VERSION 5.7 ;
  NOWIREEXTENSIONATPIN ON ;
  DIVIDERCHAR "/" ;
  BUSBITCHARS "[]" ;
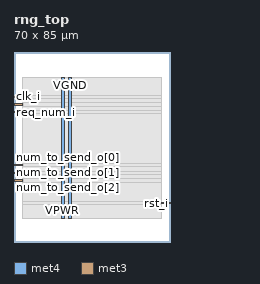
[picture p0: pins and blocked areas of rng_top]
MACRO rng_top
  CLASS BLOCK ;
  FOREIGN rng_top ;
  ORIGIN 0.000 0.000 ;
  SIZE 70.000 BY 85.000 ;
  PIN VGND
    DIRECTION INOUT ;
    USE GROUND ;
    PORT
      LAYER met4 ;
        RECT 24.340 10.640 25.940 73.680 ;
    END
  END VGND
  PIN VPWR
    DIRECTION INOUT ;
    USE POWER ;
    PORT
      LAYER met4 ;
        RECT 21.040 10.640 22.640 73.680 ;
    END
  END VPWR
  PIN clk_i
    DIRECTION INPUT ;
    USE SIGNAL ;
    ANTENNAGATEAREA 0.852000 ;
    PORT
      LAYER met3 ;
        RECT 0.000 64.640 4.000 65.240 ;
    END
  END clk_i
  PIN num_to_send_o[0]
    DIRECTION OUTPUT ;
    USE SIGNAL ;
    ANTENNADIFFAREA 0.445500 ;
    PORT
      LAYER met3 ;
        RECT 0.000 34.040 4.000 34.640 ;
    END
  END num_to_send_o[0]
  PIN num_to_send_o[1]
    DIRECTION OUTPUT ;
    USE SIGNAL ;
    ANTENNADIFFAREA 0.445500 ;
    PORT
      LAYER met3 ;
        RECT 0.000 30.640 4.000 31.240 ;
    END
  END num_to_send_o[1]
  PIN num_to_send_o[2]
    DIRECTION OUTPUT ;
    USE SIGNAL ;
    ANTENNADIFFAREA 0.445500 ;
    PORT
      LAYER met3 ;
        RECT 0.000 27.240 4.000 27.840 ;
    END
  END num_to_send_o[2]
  PIN req_num_i
    DIRECTION INPUT ;
    USE SIGNAL ;
    ANTENNAGATEAREA 0.196500 ;
    PORT
      LAYER met3 ;
        RECT 0.000 57.840 4.000 58.440 ;
    END
  END req_num_i
  PIN rst_i
    DIRECTION INPUT ;
    USE SIGNAL ;
    ANTENNAGATEAREA 0.196500 ;
    PORT
      LAYER met3 ;
        RECT 66.000 17.040 70.000 17.640 ;
    END
  END rst_i
  PIN wr_i
    DIRECTION INPUT ;
    USE SIGNAL ;
    ANTENNAGATEAREA 0.196500 ;
    PORT
      LAYER met3 ;
        RECT 0.000 61.240 4.000 61.840 ;
    END
  END wr_i
  OBS
      LAYER nwell ;
        RECT 5.330 10.795 64.590 73.630 ;
      LAYER li1 ;
        RECT 5.520 10.795 64.400 73.525 ;
      LAYER met1 ;
        RECT 4.210 10.640 64.400 73.680 ;
      LAYER met2 ;
        RECT 4.230 10.695 62.930 73.625 ;
      LAYER met3 ;
        RECT 3.990 65.640 66.000 73.605 ;
        RECT 4.400 64.240 66.000 65.640 ;
        RECT 3.990 62.240 66.000 64.240 ;
        RECT 4.400 60.840 66.000 62.240 ;
        RECT 3.990 58.840 66.000 60.840 ;
        RECT 4.400 57.440 66.000 58.840 ;
        RECT 3.990 35.040 66.000 57.440 ;
        RECT 4.400 33.640 66.000 35.040 ;
        RECT 3.990 31.640 66.000 33.640 ;
        RECT 4.400 30.240 66.000 31.640 ;
        RECT 3.990 28.240 66.000 30.240 ;
        RECT 4.400 26.840 66.000 28.240 ;
        RECT 3.990 18.040 66.000 26.840 ;
        RECT 3.990 16.640 65.600 18.040 ;
        RECT 3.990 10.715 66.000 16.640 ;
  END
END rng_top
END LIBRARY

